VERSION 5.7 ;
BUSBITCHARS "[]" ;
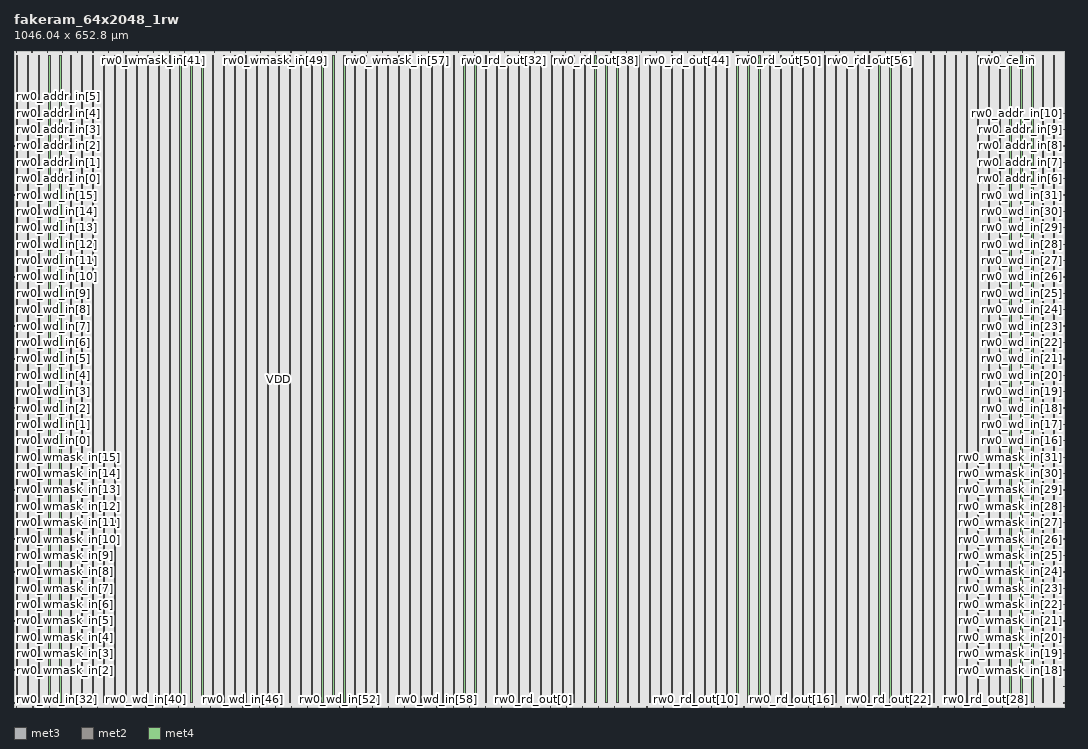
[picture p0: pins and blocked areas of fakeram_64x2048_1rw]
MACRO fakeram_64x2048_1rw
  FOREIGN fakeram_64x2048_1rw 0 0 ;
  SYMMETRY X Y R90 ;
  SIZE 1046.040 BY 652.800 ;
  CLASS BLOCK ;
  PIN rw0_wmask_in[0]
    DIRECTION INPUT ;
    USE SIGNAL ;
    SHAPE ABUTMENT ;
    PORT
      LAYER met3 ;
      RECT 0.000 3.930 0.900 4.230 ;
    END
  END rw0_wmask_in[0]
  PIN rw0_wmask_in[1]
    DIRECTION INPUT ;
    USE SIGNAL ;
    SHAPE ABUTMENT ;
    PORT
      LAYER met3 ;
      RECT 0.000 20.250 0.900 20.550 ;
    END
  END rw0_wmask_in[1]
  PIN rw0_wmask_in[2]
    DIRECTION INPUT ;
    USE SIGNAL ;
    SHAPE ABUTMENT ;
    PORT
      LAYER met3 ;
      RECT 0.000 36.570 0.900 36.870 ;
    END
  END rw0_wmask_in[2]
  PIN rw0_wmask_in[3]
    DIRECTION INPUT ;
    USE SIGNAL ;
    SHAPE ABUTMENT ;
    PORT
      LAYER met3 ;
      RECT 0.000 52.890 0.900 53.190 ;
    END
  END rw0_wmask_in[3]
  PIN rw0_wmask_in[4]
    DIRECTION INPUT ;
    USE SIGNAL ;
    SHAPE ABUTMENT ;
    PORT
      LAYER met3 ;
      RECT 0.000 69.210 0.900 69.510 ;
    END
  END rw0_wmask_in[4]
  PIN rw0_wmask_in[5]
    DIRECTION INPUT ;
    USE SIGNAL ;
    SHAPE ABUTMENT ;
    PORT
      LAYER met3 ;
      RECT 0.000 85.530 0.900 85.830 ;
    END
  END rw0_wmask_in[5]
  PIN rw0_wmask_in[6]
    DIRECTION INPUT ;
    USE SIGNAL ;
    SHAPE ABUTMENT ;
    PORT
      LAYER met3 ;
      RECT 0.000 101.850 0.900 102.150 ;
    END
  END rw0_wmask_in[6]
  PIN rw0_wmask_in[7]
    DIRECTION INPUT ;
    USE SIGNAL ;
    SHAPE ABUTMENT ;
    PORT
      LAYER met3 ;
      RECT 0.000 118.170 0.900 118.470 ;
    END
  END rw0_wmask_in[7]
  PIN rw0_wmask_in[8]
    DIRECTION INPUT ;
    USE SIGNAL ;
    SHAPE ABUTMENT ;
    PORT
      LAYER met3 ;
      RECT 0.000 134.490 0.900 134.790 ;
    END
  END rw0_wmask_in[8]
  PIN rw0_wmask_in[9]
    DIRECTION INPUT ;
    USE SIGNAL ;
    SHAPE ABUTMENT ;
    PORT
      LAYER met3 ;
      RECT 0.000 150.810 0.900 151.110 ;
    END
  END rw0_wmask_in[9]
  PIN rw0_wmask_in[10]
    DIRECTION INPUT ;
    USE SIGNAL ;
    SHAPE ABUTMENT ;
    PORT
      LAYER met3 ;
      RECT 0.000 167.130 0.900 167.430 ;
    END
  END rw0_wmask_in[10]
  PIN rw0_wmask_in[11]
    DIRECTION INPUT ;
    USE SIGNAL ;
    SHAPE ABUTMENT ;
    PORT
      LAYER met3 ;
      RECT 0.000 183.450 0.900 183.750 ;
    END
  END rw0_wmask_in[11]
  PIN rw0_wmask_in[12]
    DIRECTION INPUT ;
    USE SIGNAL ;
    SHAPE ABUTMENT ;
    PORT
      LAYER met3 ;
      RECT 0.000 199.770 0.900 200.070 ;
    END
  END rw0_wmask_in[12]
  PIN rw0_wmask_in[13]
    DIRECTION INPUT ;
    USE SIGNAL ;
    SHAPE ABUTMENT ;
    PORT
      LAYER met3 ;
      RECT 0.000 216.090 0.900 216.390 ;
    END
  END rw0_wmask_in[13]
  PIN rw0_wmask_in[14]
    DIRECTION INPUT ;
    USE SIGNAL ;
    SHAPE ABUTMENT ;
    PORT
      LAYER met3 ;
      RECT 0.000 232.410 0.900 232.710 ;
    END
  END rw0_wmask_in[14]
  PIN rw0_wmask_in[15]
    DIRECTION INPUT ;
    USE SIGNAL ;
    SHAPE ABUTMENT ;
    PORT
      LAYER met3 ;
      RECT 0.000 248.730 0.900 249.030 ;
    END
  END rw0_wmask_in[15]
  PIN rw0_wmask_in[16]
    DIRECTION INPUT ;
    USE SIGNAL ;
    SHAPE ABUTMENT ;
    PORT
      LAYER met3 ;
      RECT 1045.140 3.930 1046.040 4.230 ;
    END
  END rw0_wmask_in[16]
  PIN rw0_wmask_in[17]
    DIRECTION INPUT ;
    USE SIGNAL ;
    SHAPE ABUTMENT ;
    PORT
      LAYER met3 ;
      RECT 1045.140 20.250 1046.040 20.550 ;
    END
  END rw0_wmask_in[17]
  PIN rw0_wmask_in[18]
    DIRECTION INPUT ;
    USE SIGNAL ;
    SHAPE ABUTMENT ;
    PORT
      LAYER met3 ;
      RECT 1045.140 36.570 1046.040 36.870 ;
    END
  END rw0_wmask_in[18]
  PIN rw0_wmask_in[19]
    DIRECTION INPUT ;
    USE SIGNAL ;
    SHAPE ABUTMENT ;
    PORT
      LAYER met3 ;
      RECT 1045.140 52.890 1046.040 53.190 ;
    END
  END rw0_wmask_in[19]
  PIN rw0_wmask_in[20]
    DIRECTION INPUT ;
    USE SIGNAL ;
    SHAPE ABUTMENT ;
    PORT
      LAYER met3 ;
      RECT 1045.140 69.210 1046.040 69.510 ;
    END
  END rw0_wmask_in[20]
  PIN rw0_wmask_in[21]
    DIRECTION INPUT ;
    USE SIGNAL ;
    SHAPE ABUTMENT ;
    PORT
      LAYER met3 ;
      RECT 1045.140 85.530 1046.040 85.830 ;
    END
  END rw0_wmask_in[21]
  PIN rw0_wmask_in[22]
    DIRECTION INPUT ;
    USE SIGNAL ;
    SHAPE ABUTMENT ;
    PORT
      LAYER met3 ;
      RECT 1045.140 101.850 1046.040 102.150 ;
    END
  END rw0_wmask_in[22]
  PIN rw0_wmask_in[23]
    DIRECTION INPUT ;
    USE SIGNAL ;
    SHAPE ABUTMENT ;
    PORT
      LAYER met3 ;
      RECT 1045.140 118.170 1046.040 118.470 ;
    END
  END rw0_wmask_in[23]
  PIN rw0_wmask_in[24]
    DIRECTION INPUT ;
    USE SIGNAL ;
    SHAPE ABUTMENT ;
    PORT
      LAYER met3 ;
      RECT 1045.140 134.490 1046.040 134.790 ;
    END
  END rw0_wmask_in[24]
  PIN rw0_wmask_in[25]
    DIRECTION INPUT ;
    USE SIGNAL ;
    SHAPE ABUTMENT ;
    PORT
      LAYER met3 ;
      RECT 1045.140 150.810 1046.040 151.110 ;
    END
  END rw0_wmask_in[25]
  PIN rw0_wmask_in[26]
    DIRECTION INPUT ;
    USE SIGNAL ;
    SHAPE ABUTMENT ;
    PORT
      LAYER met3 ;
      RECT 1045.140 167.130 1046.040 167.430 ;
    END
  END rw0_wmask_in[26]
  PIN rw0_wmask_in[27]
    DIRECTION INPUT ;
    USE SIGNAL ;
    SHAPE ABUTMENT ;
    PORT
      LAYER met3 ;
      RECT 1045.140 183.450 1046.040 183.750 ;
    END
  END rw0_wmask_in[27]
  PIN rw0_wmask_in[28]
    DIRECTION INPUT ;
    USE SIGNAL ;
    SHAPE ABUTMENT ;
    PORT
      LAYER met3 ;
      RECT 1045.140 199.770 1046.040 200.070 ;
    END
  END rw0_wmask_in[28]
  PIN rw0_wmask_in[29]
    DIRECTION INPUT ;
    USE SIGNAL ;
    SHAPE ABUTMENT ;
    PORT
      LAYER met3 ;
      RECT 1045.140 216.090 1046.040 216.390 ;
    END
  END rw0_wmask_in[29]
  PIN rw0_wmask_in[30]
    DIRECTION INPUT ;
    USE SIGNAL ;
    SHAPE ABUTMENT ;
    PORT
      LAYER met3 ;
      RECT 1045.140 232.410 1046.040 232.710 ;
    END
  END rw0_wmask_in[30]
  PIN rw0_wmask_in[31]
    DIRECTION INPUT ;
    USE SIGNAL ;
    SHAPE ABUTMENT ;
    PORT
      LAYER met3 ;
      RECT 1045.140 248.730 1046.040 249.030 ;
    END
  END rw0_wmask_in[31]
  PIN rw0_wmask_in[32]
    DIRECTION INPUT ;
    USE SIGNAL ;
    SHAPE ABUTMENT ;
    PORT
      LAYER met2 ;
      RECT 2.690 652.380 2.830 652.800 ;
    END
  END rw0_wmask_in[32]
  PIN rw0_wmask_in[33]
    DIRECTION INPUT ;
    USE SIGNAL ;
    SHAPE ABUTMENT ;
    PORT
      LAYER met2 ;
      RECT 17.870 652.380 18.010 652.800 ;
    END
  END rw0_wmask_in[33]
  PIN rw0_wmask_in[34]
    DIRECTION INPUT ;
    USE SIGNAL ;
    SHAPE ABUTMENT ;
    PORT
      LAYER met2 ;
      RECT 33.050 652.380 33.190 652.800 ;
    END
  END rw0_wmask_in[34]
  PIN rw0_wmask_in[35]
    DIRECTION INPUT ;
    USE SIGNAL ;
    SHAPE ABUTMENT ;
    PORT
      LAYER met2 ;
      RECT 48.230 652.380 48.370 652.800 ;
    END
  END rw0_wmask_in[35]
  PIN rw0_wmask_in[36]
    DIRECTION INPUT ;
    USE SIGNAL ;
    SHAPE ABUTMENT ;
    PORT
      LAYER met2 ;
      RECT 63.410 652.380 63.550 652.800 ;
    END
  END rw0_wmask_in[36]
  PIN rw0_wmask_in[37]
    DIRECTION INPUT ;
    USE SIGNAL ;
    SHAPE ABUTMENT ;
    PORT
      LAYER met2 ;
      RECT 78.590 652.380 78.730 652.800 ;
    END
  END rw0_wmask_in[37]
  PIN rw0_wmask_in[38]
    DIRECTION INPUT ;
    USE SIGNAL ;
    SHAPE ABUTMENT ;
    PORT
      LAYER met2 ;
      RECT 93.770 652.380 93.910 652.800 ;
    END
  END rw0_wmask_in[38]
  PIN rw0_wmask_in[39]
    DIRECTION INPUT ;
    USE SIGNAL ;
    SHAPE ABUTMENT ;
    PORT
      LAYER met2 ;
      RECT 108.950 652.380 109.090 652.800 ;
    END
  END rw0_wmask_in[39]
  PIN rw0_wmask_in[40]
    DIRECTION INPUT ;
    USE SIGNAL ;
    SHAPE ABUTMENT ;
    PORT
      LAYER met2 ;
      RECT 124.130 652.380 124.270 652.800 ;
    END
  END rw0_wmask_in[40]
  PIN rw0_wmask_in[41]
    DIRECTION INPUT ;
    USE SIGNAL ;
    SHAPE ABUTMENT ;
    PORT
      LAYER met2 ;
      RECT 139.310 652.380 139.450 652.800 ;
    END
  END rw0_wmask_in[41]
  PIN rw0_wmask_in[42]
    DIRECTION INPUT ;
    USE SIGNAL ;
    SHAPE ABUTMENT ;
    PORT
      LAYER met2 ;
      RECT 154.490 652.380 154.630 652.800 ;
    END
  END rw0_wmask_in[42]
  PIN rw0_wmask_in[43]
    DIRECTION INPUT ;
    USE SIGNAL ;
    SHAPE ABUTMENT ;
    PORT
      LAYER met2 ;
      RECT 169.670 652.380 169.810 652.800 ;
    END
  END rw0_wmask_in[43]
  PIN rw0_wmask_in[44]
    DIRECTION INPUT ;
    USE SIGNAL ;
    SHAPE ABUTMENT ;
    PORT
      LAYER met2 ;
      RECT 184.850 652.380 184.990 652.800 ;
    END
  END rw0_wmask_in[44]
  PIN rw0_wmask_in[45]
    DIRECTION INPUT ;
    USE SIGNAL ;
    SHAPE ABUTMENT ;
    PORT
      LAYER met2 ;
      RECT 200.030 652.380 200.170 652.800 ;
    END
  END rw0_wmask_in[45]
  PIN rw0_wmask_in[46]
    DIRECTION INPUT ;
    USE SIGNAL ;
    SHAPE ABUTMENT ;
    PORT
      LAYER met2 ;
      RECT 215.210 652.380 215.350 652.800 ;
    END
  END rw0_wmask_in[46]
  PIN rw0_wmask_in[47]
    DIRECTION INPUT ;
    USE SIGNAL ;
    SHAPE ABUTMENT ;
    PORT
      LAYER met2 ;
      RECT 230.390 652.380 230.530 652.800 ;
    END
  END rw0_wmask_in[47]
  PIN rw0_wmask_in[48]
    DIRECTION INPUT ;
    USE SIGNAL ;
    SHAPE ABUTMENT ;
    PORT
      LAYER met2 ;
      RECT 245.570 652.380 245.710 652.800 ;
    END
  END rw0_wmask_in[48]
  PIN rw0_wmask_in[49]
    DIRECTION INPUT ;
    USE SIGNAL ;
    SHAPE ABUTMENT ;
    PORT
      LAYER met2 ;
      RECT 260.750 652.380 260.890 652.800 ;
    END
  END rw0_wmask_in[49]
  PIN rw0_wmask_in[50]
    DIRECTION INPUT ;
    USE SIGNAL ;
    SHAPE ABUTMENT ;
    PORT
      LAYER met2 ;
      RECT 275.930 652.380 276.070 652.800 ;
    END
  END rw0_wmask_in[50]
  PIN rw0_wmask_in[51]
    DIRECTION INPUT ;
    USE SIGNAL ;
    SHAPE ABUTMENT ;
    PORT
      LAYER met2 ;
      RECT 291.110 652.380 291.250 652.800 ;
    END
  END rw0_wmask_in[51]
  PIN rw0_wmask_in[52]
    DIRECTION INPUT ;
    USE SIGNAL ;
    SHAPE ABUTMENT ;
    PORT
      LAYER met2 ;
      RECT 306.290 652.380 306.430 652.800 ;
    END
  END rw0_wmask_in[52]
  PIN rw0_wmask_in[53]
    DIRECTION INPUT ;
    USE SIGNAL ;
    SHAPE ABUTMENT ;
    PORT
      LAYER met2 ;
      RECT 321.470 652.380 321.610 652.800 ;
    END
  END rw0_wmask_in[53]
  PIN rw0_wmask_in[54]
    DIRECTION INPUT ;
    USE SIGNAL ;
    SHAPE ABUTMENT ;
    PORT
      LAYER met2 ;
      RECT 336.650 652.380 336.790 652.800 ;
    END
  END rw0_wmask_in[54]
  PIN rw0_wmask_in[55]
    DIRECTION INPUT ;
    USE SIGNAL ;
    SHAPE ABUTMENT ;
    PORT
      LAYER met2 ;
      RECT 351.830 652.380 351.970 652.800 ;
    END
  END rw0_wmask_in[55]
  PIN rw0_wmask_in[56]
    DIRECTION INPUT ;
    USE SIGNAL ;
    SHAPE ABUTMENT ;
    PORT
      LAYER met2 ;
      RECT 367.010 652.380 367.150 652.800 ;
    END
  END rw0_wmask_in[56]
  PIN rw0_wmask_in[57]
    DIRECTION INPUT ;
    USE SIGNAL ;
    SHAPE ABUTMENT ;
    PORT
      LAYER met2 ;
      RECT 382.190 652.380 382.330 652.800 ;
    END
  END rw0_wmask_in[57]
  PIN rw0_wmask_in[58]
    DIRECTION INPUT ;
    USE SIGNAL ;
    SHAPE ABUTMENT ;
    PORT
      LAYER met2 ;
      RECT 397.370 652.380 397.510 652.800 ;
    END
  END rw0_wmask_in[58]
  PIN rw0_wmask_in[59]
    DIRECTION INPUT ;
    USE SIGNAL ;
    SHAPE ABUTMENT ;
    PORT
      LAYER met2 ;
      RECT 412.550 652.380 412.690 652.800 ;
    END
  END rw0_wmask_in[59]
  PIN rw0_wmask_in[60]
    DIRECTION INPUT ;
    USE SIGNAL ;
    SHAPE ABUTMENT ;
    PORT
      LAYER met2 ;
      RECT 427.730 652.380 427.870 652.800 ;
    END
  END rw0_wmask_in[60]
  PIN rw0_wmask_in[61]
    DIRECTION INPUT ;
    USE SIGNAL ;
    SHAPE ABUTMENT ;
    PORT
      LAYER met2 ;
      RECT 442.910 652.380 443.050 652.800 ;
    END
  END rw0_wmask_in[61]
  PIN rw0_wmask_in[62]
    DIRECTION INPUT ;
    USE SIGNAL ;
    SHAPE ABUTMENT ;
    PORT
      LAYER met2 ;
      RECT 458.090 652.380 458.230 652.800 ;
    END
  END rw0_wmask_in[62]
  PIN rw0_wmask_in[63]
    DIRECTION INPUT ;
    USE SIGNAL ;
    SHAPE ABUTMENT ;
    PORT
      LAYER met2 ;
      RECT 473.270 652.380 473.410 652.800 ;
    END
  END rw0_wmask_in[63]
  PIN rw0_wd_in[0]
    DIRECTION INPUT ;
    USE SIGNAL ;
    SHAPE ABUTMENT ;
    PORT
      LAYER met3 ;
      RECT 0.000 265.050 0.900 265.350 ;
    END
  END rw0_wd_in[0]
  PIN rw0_wd_in[1]
    DIRECTION INPUT ;
    USE SIGNAL ;
    SHAPE ABUTMENT ;
    PORT
      LAYER met3 ;
      RECT 0.000 281.370 0.900 281.670 ;
    END
  END rw0_wd_in[1]
  PIN rw0_wd_in[2]
    DIRECTION INPUT ;
    USE SIGNAL ;
    SHAPE ABUTMENT ;
    PORT
      LAYER met3 ;
      RECT 0.000 297.690 0.900 297.990 ;
    END
  END rw0_wd_in[2]
  PIN rw0_wd_in[3]
    DIRECTION INPUT ;
    USE SIGNAL ;
    SHAPE ABUTMENT ;
    PORT
      LAYER met3 ;
      RECT 0.000 314.010 0.900 314.310 ;
    END
  END rw0_wd_in[3]
  PIN rw0_wd_in[4]
    DIRECTION INPUT ;
    USE SIGNAL ;
    SHAPE ABUTMENT ;
    PORT
      LAYER met3 ;
      RECT 0.000 330.330 0.900 330.630 ;
    END
  END rw0_wd_in[4]
  PIN rw0_wd_in[5]
    DIRECTION INPUT ;
    USE SIGNAL ;
    SHAPE ABUTMENT ;
    PORT
      LAYER met3 ;
      RECT 0.000 346.650 0.900 346.950 ;
    END
  END rw0_wd_in[5]
  PIN rw0_wd_in[6]
    DIRECTION INPUT ;
    USE SIGNAL ;
    SHAPE ABUTMENT ;
    PORT
      LAYER met3 ;
      RECT 0.000 362.970 0.900 363.270 ;
    END
  END rw0_wd_in[6]
  PIN rw0_wd_in[7]
    DIRECTION INPUT ;
    USE SIGNAL ;
    SHAPE ABUTMENT ;
    PORT
      LAYER met3 ;
      RECT 0.000 379.290 0.900 379.590 ;
    END
  END rw0_wd_in[7]
  PIN rw0_wd_in[8]
    DIRECTION INPUT ;
    USE SIGNAL ;
    SHAPE ABUTMENT ;
    PORT
      LAYER met3 ;
      RECT 0.000 395.610 0.900 395.910 ;
    END
  END rw0_wd_in[8]
  PIN rw0_wd_in[9]
    DIRECTION INPUT ;
    USE SIGNAL ;
    SHAPE ABUTMENT ;
    PORT
      LAYER met3 ;
      RECT 0.000 411.930 0.900 412.230 ;
    END
  END rw0_wd_in[9]
  PIN rw0_wd_in[10]
    DIRECTION INPUT ;
    USE SIGNAL ;
    SHAPE ABUTMENT ;
    PORT
      LAYER met3 ;
      RECT 0.000 428.250 0.900 428.550 ;
    END
  END rw0_wd_in[10]
  PIN rw0_wd_in[11]
    DIRECTION INPUT ;
    USE SIGNAL ;
    SHAPE ABUTMENT ;
    PORT
      LAYER met3 ;
      RECT 0.000 444.570 0.900 444.870 ;
    END
  END rw0_wd_in[11]
  PIN rw0_wd_in[12]
    DIRECTION INPUT ;
    USE SIGNAL ;
    SHAPE ABUTMENT ;
    PORT
      LAYER met3 ;
      RECT 0.000 460.890 0.900 461.190 ;
    END
  END rw0_wd_in[12]
  PIN rw0_wd_in[13]
    DIRECTION INPUT ;
    USE SIGNAL ;
    SHAPE ABUTMENT ;
    PORT
      LAYER met3 ;
      RECT 0.000 477.210 0.900 477.510 ;
    END
  END rw0_wd_in[13]
  PIN rw0_wd_in[14]
    DIRECTION INPUT ;
    USE SIGNAL ;
    SHAPE ABUTMENT ;
    PORT
      LAYER met3 ;
      RECT 0.000 493.530 0.900 493.830 ;
    END
  END rw0_wd_in[14]
  PIN rw0_wd_in[15]
    DIRECTION INPUT ;
    USE SIGNAL ;
    SHAPE ABUTMENT ;
    PORT
      LAYER met3 ;
      RECT 0.000 509.850 0.900 510.150 ;
    END
  END rw0_wd_in[15]
  PIN rw0_wd_in[16]
    DIRECTION INPUT ;
    USE SIGNAL ;
    SHAPE ABUTMENT ;
    PORT
      LAYER met3 ;
      RECT 1045.140 265.050 1046.040 265.350 ;
    END
  END rw0_wd_in[16]
  PIN rw0_wd_in[17]
    DIRECTION INPUT ;
    USE SIGNAL ;
    SHAPE ABUTMENT ;
    PORT
      LAYER met3 ;
      RECT 1045.140 281.370 1046.040 281.670 ;
    END
  END rw0_wd_in[17]
  PIN rw0_wd_in[18]
    DIRECTION INPUT ;
    USE SIGNAL ;
    SHAPE ABUTMENT ;
    PORT
      LAYER met3 ;
      RECT 1045.140 297.690 1046.040 297.990 ;
    END
  END rw0_wd_in[18]
  PIN rw0_wd_in[19]
    DIRECTION INPUT ;
    USE SIGNAL ;
    SHAPE ABUTMENT ;
    PORT
      LAYER met3 ;
      RECT 1045.140 314.010 1046.040 314.310 ;
    END
  END rw0_wd_in[19]
  PIN rw0_wd_in[20]
    DIRECTION INPUT ;
    USE SIGNAL ;
    SHAPE ABUTMENT ;
    PORT
      LAYER met3 ;
      RECT 1045.140 330.330 1046.040 330.630 ;
    END
  END rw0_wd_in[20]
  PIN rw0_wd_in[21]
    DIRECTION INPUT ;
    USE SIGNAL ;
    SHAPE ABUTMENT ;
    PORT
      LAYER met3 ;
      RECT 1045.140 346.650 1046.040 346.950 ;
    END
  END rw0_wd_in[21]
  PIN rw0_wd_in[22]
    DIRECTION INPUT ;
    USE SIGNAL ;
    SHAPE ABUTMENT ;
    PORT
      LAYER met3 ;
      RECT 1045.140 362.970 1046.040 363.270 ;
    END
  END rw0_wd_in[22]
  PIN rw0_wd_in[23]
    DIRECTION INPUT ;
    USE SIGNAL ;
    SHAPE ABUTMENT ;
    PORT
      LAYER met3 ;
      RECT 1045.140 379.290 1046.040 379.590 ;
    END
  END rw0_wd_in[23]
  PIN rw0_wd_in[24]
    DIRECTION INPUT ;
    USE SIGNAL ;
    SHAPE ABUTMENT ;
    PORT
      LAYER met3 ;
      RECT 1045.140 395.610 1046.040 395.910 ;
    END
  END rw0_wd_in[24]
  PIN rw0_wd_in[25]
    DIRECTION INPUT ;
    USE SIGNAL ;
    SHAPE ABUTMENT ;
    PORT
      LAYER met3 ;
      RECT 1045.140 411.930 1046.040 412.230 ;
    END
  END rw0_wd_in[25]
  PIN rw0_wd_in[26]
    DIRECTION INPUT ;
    USE SIGNAL ;
    SHAPE ABUTMENT ;
    PORT
      LAYER met3 ;
      RECT 1045.140 428.250 1046.040 428.550 ;
    END
  END rw0_wd_in[26]
  PIN rw0_wd_in[27]
    DIRECTION INPUT ;
    USE SIGNAL ;
    SHAPE ABUTMENT ;
    PORT
      LAYER met3 ;
      RECT 1045.140 444.570 1046.040 444.870 ;
    END
  END rw0_wd_in[27]
  PIN rw0_wd_in[28]
    DIRECTION INPUT ;
    USE SIGNAL ;
    SHAPE ABUTMENT ;
    PORT
      LAYER met3 ;
      RECT 1045.140 460.890 1046.040 461.190 ;
    END
  END rw0_wd_in[28]
  PIN rw0_wd_in[29]
    DIRECTION INPUT ;
    USE SIGNAL ;
    SHAPE ABUTMENT ;
    PORT
      LAYER met3 ;
      RECT 1045.140 477.210 1046.040 477.510 ;
    END
  END rw0_wd_in[29]
  PIN rw0_wd_in[30]
    DIRECTION INPUT ;
    USE SIGNAL ;
    SHAPE ABUTMENT ;
    PORT
      LAYER met3 ;
      RECT 1045.140 493.530 1046.040 493.830 ;
    END
  END rw0_wd_in[30]
  PIN rw0_wd_in[31]
    DIRECTION INPUT ;
    USE SIGNAL ;
    SHAPE ABUTMENT ;
    PORT
      LAYER met3 ;
      RECT 1045.140 509.850 1046.040 510.150 ;
    END
  END rw0_wd_in[31]
  PIN rw0_wd_in[32]
    DIRECTION OUTPUT ;
    USE SIGNAL ;
    SHAPE ABUTMENT ;
    PORT
      LAYER met2 ;
      RECT 2.690 0.000 2.830 0.420 ;
    END
  END rw0_wd_in[32]
  PIN rw0_wd_in[33]
    DIRECTION OUTPUT ;
    USE SIGNAL ;
    SHAPE ABUTMENT ;
    PORT
      LAYER met2 ;
      RECT 18.790 0.000 18.930 0.420 ;
    END
  END rw0_wd_in[33]
  PIN rw0_wd_in[34]
    DIRECTION OUTPUT ;
    USE SIGNAL ;
    SHAPE ABUTMENT ;
    PORT
      LAYER met2 ;
      RECT 34.890 0.000 35.030 0.420 ;
    END
  END rw0_wd_in[34]
  PIN rw0_wd_in[35]
    DIRECTION OUTPUT ;
    USE SIGNAL ;
    SHAPE ABUTMENT ;
    PORT
      LAYER met2 ;
      RECT 50.990 0.000 51.130 0.420 ;
    END
  END rw0_wd_in[35]
  PIN rw0_wd_in[36]
    DIRECTION OUTPUT ;
    USE SIGNAL ;
    SHAPE ABUTMENT ;
    PORT
      LAYER met2 ;
      RECT 67.090 0.000 67.230 0.420 ;
    END
  END rw0_wd_in[36]
  PIN rw0_wd_in[37]
    DIRECTION OUTPUT ;
    USE SIGNAL ;
    SHAPE ABUTMENT ;
    PORT
      LAYER met2 ;
      RECT 83.190 0.000 83.330 0.420 ;
    END
  END rw0_wd_in[37]
  PIN rw0_wd_in[38]
    DIRECTION OUTPUT ;
    USE SIGNAL ;
    SHAPE ABUTMENT ;
    PORT
      LAYER met2 ;
      RECT 99.290 0.000 99.430 0.420 ;
    END
  END rw0_wd_in[38]
  PIN rw0_wd_in[39]
    DIRECTION OUTPUT ;
    USE SIGNAL ;
    SHAPE ABUTMENT ;
    PORT
      LAYER met2 ;
      RECT 115.390 0.000 115.530 0.420 ;
    END
  END rw0_wd_in[39]
  PIN rw0_wd_in[40]
    DIRECTION OUTPUT ;
    USE SIGNAL ;
    SHAPE ABUTMENT ;
    PORT
      LAYER met2 ;
      RECT 131.490 0.000 131.630 0.420 ;
    END
  END rw0_wd_in[40]
  PIN rw0_wd_in[41]
    DIRECTION OUTPUT ;
    USE SIGNAL ;
    SHAPE ABUTMENT ;
    PORT
      LAYER met2 ;
      RECT 147.590 0.000 147.730 0.420 ;
    END
  END rw0_wd_in[41]
  PIN rw0_wd_in[42]
    DIRECTION OUTPUT ;
    USE SIGNAL ;
    SHAPE ABUTMENT ;
    PORT
      LAYER met2 ;
      RECT 163.690 0.000 163.830 0.420 ;
    END
  END rw0_wd_in[42]
  PIN rw0_wd_in[43]
    DIRECTION OUTPUT ;
    USE SIGNAL ;
    SHAPE ABUTMENT ;
    PORT
      LAYER met2 ;
      RECT 179.790 0.000 179.930 0.420 ;
    END
  END rw0_wd_in[43]
  PIN rw0_wd_in[44]
    DIRECTION OUTPUT ;
    USE SIGNAL ;
    SHAPE ABUTMENT ;
    PORT
      LAYER met2 ;
      RECT 195.890 0.000 196.030 0.420 ;
    END
  END rw0_wd_in[44]
  PIN rw0_wd_in[45]
    DIRECTION OUTPUT ;
    USE SIGNAL ;
    SHAPE ABUTMENT ;
    PORT
      LAYER met2 ;
      RECT 211.990 0.000 212.130 0.420 ;
    END
  END rw0_wd_in[45]
  PIN rw0_wd_in[46]
    DIRECTION OUTPUT ;
    USE SIGNAL ;
    SHAPE ABUTMENT ;
    PORT
      LAYER met2 ;
      RECT 228.090 0.000 228.230 0.420 ;
    END
  END rw0_wd_in[46]
  PIN rw0_wd_in[47]
    DIRECTION OUTPUT ;
    USE SIGNAL ;
    SHAPE ABUTMENT ;
    PORT
      LAYER met2 ;
      RECT 244.190 0.000 244.330 0.420 ;
    END
  END rw0_wd_in[47]
  PIN rw0_wd_in[48]
    DIRECTION OUTPUT ;
    USE SIGNAL ;
    SHAPE ABUTMENT ;
    PORT
      LAYER met2 ;
      RECT 260.290 0.000 260.430 0.420 ;
    END
  END rw0_wd_in[48]
  PIN rw0_wd_in[49]
    DIRECTION OUTPUT ;
    USE SIGNAL ;
    SHAPE ABUTMENT ;
    PORT
      LAYER met2 ;
      RECT 276.390 0.000 276.530 0.420 ;
    END
  END rw0_wd_in[49]
  PIN rw0_wd_in[50]
    DIRECTION OUTPUT ;
    USE SIGNAL ;
    SHAPE ABUTMENT ;
    PORT
      LAYER met2 ;
      RECT 292.490 0.000 292.630 0.420 ;
    END
  END rw0_wd_in[50]
  PIN rw0_wd_in[51]
    DIRECTION OUTPUT ;
    USE SIGNAL ;
    SHAPE ABUTMENT ;
    PORT
      LAYER met2 ;
      RECT 308.590 0.000 308.730 0.420 ;
    END
  END rw0_wd_in[51]
  PIN rw0_wd_in[52]
    DIRECTION OUTPUT ;
    USE SIGNAL ;
    SHAPE ABUTMENT ;
    PORT
      LAYER met2 ;
      RECT 324.690 0.000 324.830 0.420 ;
    END
  END rw0_wd_in[52]
  PIN rw0_wd_in[53]
    DIRECTION OUTPUT ;
    USE SIGNAL ;
    SHAPE ABUTMENT ;
    PORT
      LAYER met2 ;
      RECT 340.790 0.000 340.930 0.420 ;
    END
  END rw0_wd_in[53]
  PIN rw0_wd_in[54]
    DIRECTION OUTPUT ;
    USE SIGNAL ;
    SHAPE ABUTMENT ;
    PORT
      LAYER met2 ;
      RECT 356.890 0.000 357.030 0.420 ;
    END
  END rw0_wd_in[54]
  PIN rw0_wd_in[55]
    DIRECTION OUTPUT ;
    USE SIGNAL ;
    SHAPE ABUTMENT ;
    PORT
      LAYER met2 ;
      RECT 372.990 0.000 373.130 0.420 ;
    END
  END rw0_wd_in[55]
  PIN rw0_wd_in[56]
    DIRECTION OUTPUT ;
    USE SIGNAL ;
    SHAPE ABUTMENT ;
    PORT
      LAYER met2 ;
      RECT 389.090 0.000 389.230 0.420 ;
    END
  END rw0_wd_in[56]
  PIN rw0_wd_in[57]
    DIRECTION OUTPUT ;
    USE SIGNAL ;
    SHAPE ABUTMENT ;
    PORT
      LAYER met2 ;
      RECT 405.190 0.000 405.330 0.420 ;
    END
  END rw0_wd_in[57]
  PIN rw0_wd_in[58]
    DIRECTION OUTPUT ;
    USE SIGNAL ;
    SHAPE ABUTMENT ;
    PORT
      LAYER met2 ;
      RECT 421.290 0.000 421.430 0.420 ;
    END
  END rw0_wd_in[58]
  PIN rw0_wd_in[59]
    DIRECTION OUTPUT ;
    USE SIGNAL ;
    SHAPE ABUTMENT ;
    PORT
      LAYER met2 ;
      RECT 437.390 0.000 437.530 0.420 ;
    END
  END rw0_wd_in[59]
  PIN rw0_wd_in[60]
    DIRECTION OUTPUT ;
    USE SIGNAL ;
    SHAPE ABUTMENT ;
    PORT
      LAYER met2 ;
      RECT 453.490 0.000 453.630 0.420 ;
    END
  END rw0_wd_in[60]
  PIN rw0_wd_in[61]
    DIRECTION OUTPUT ;
    USE SIGNAL ;
    SHAPE ABUTMENT ;
    PORT
      LAYER met2 ;
      RECT 469.590 0.000 469.730 0.420 ;
    END
  END rw0_wd_in[61]
  PIN rw0_wd_in[62]
    DIRECTION OUTPUT ;
    USE SIGNAL ;
    SHAPE ABUTMENT ;
    PORT
      LAYER met2 ;
      RECT 485.690 0.000 485.830 0.420 ;
    END
  END rw0_wd_in[62]
  PIN rw0_wd_in[63]
    DIRECTION OUTPUT ;
    USE SIGNAL ;
    SHAPE ABUTMENT ;
    PORT
      LAYER met2 ;
      RECT 501.790 0.000 501.930 0.420 ;
    END
  END rw0_wd_in[63]
  PIN rw0_rd_out[0]
    DIRECTION OUTPUT ;
    USE SIGNAL ;
    SHAPE ABUTMENT ;
    PORT
      LAYER met2 ;
      RECT 517.890 0.000 518.030 0.420 ;
    END
  END rw0_rd_out[0]
  PIN rw0_rd_out[1]
    DIRECTION OUTPUT ;
    USE SIGNAL ;
    SHAPE ABUTMENT ;
    PORT
      LAYER met2 ;
      RECT 533.990 0.000 534.130 0.420 ;
    END
  END rw0_rd_out[1]
  PIN rw0_rd_out[2]
    DIRECTION OUTPUT ;
    USE SIGNAL ;
    SHAPE ABUTMENT ;
    PORT
      LAYER met2 ;
      RECT 550.090 0.000 550.230 0.420 ;
    END
  END rw0_rd_out[2]
  PIN rw0_rd_out[3]
    DIRECTION OUTPUT ;
    USE SIGNAL ;
    SHAPE ABUTMENT ;
    PORT
      LAYER met2 ;
      RECT 566.190 0.000 566.330 0.420 ;
    END
  END rw0_rd_out[3]
  PIN rw0_rd_out[4]
    DIRECTION OUTPUT ;
    USE SIGNAL ;
    SHAPE ABUTMENT ;
    PORT
      LAYER met2 ;
      RECT 582.290 0.000 582.430 0.420 ;
    END
  END rw0_rd_out[4]
  PIN rw0_rd_out[5]
    DIRECTION OUTPUT ;
    USE SIGNAL ;
    SHAPE ABUTMENT ;
    PORT
      LAYER met2 ;
      RECT 598.390 0.000 598.530 0.420 ;
    END
  END rw0_rd_out[5]
  PIN rw0_rd_out[6]
    DIRECTION OUTPUT ;
    USE SIGNAL ;
    SHAPE ABUTMENT ;
    PORT
      LAYER met2 ;
      RECT 614.490 0.000 614.630 0.420 ;
    END
  END rw0_rd_out[6]
  PIN rw0_rd_out[7]
    DIRECTION OUTPUT ;
    USE SIGNAL ;
    SHAPE ABUTMENT ;
    PORT
      LAYER met2 ;
      RECT 630.590 0.000 630.730 0.420 ;
    END
  END rw0_rd_out[7]
  PIN rw0_rd_out[8]
    DIRECTION OUTPUT ;
    USE SIGNAL ;
    SHAPE ABUTMENT ;
    PORT
      LAYER met2 ;
      RECT 646.690 0.000 646.830 0.420 ;
    END
  END rw0_rd_out[8]
  PIN rw0_rd_out[9]
    DIRECTION OUTPUT ;
    USE SIGNAL ;
    SHAPE ABUTMENT ;
    PORT
      LAYER met2 ;
      RECT 662.790 0.000 662.930 0.420 ;
    END
  END rw0_rd_out[9]
  PIN rw0_rd_out[10]
    DIRECTION OUTPUT ;
    USE SIGNAL ;
    SHAPE ABUTMENT ;
    PORT
      LAYER met2 ;
      RECT 678.890 0.000 679.030 0.420 ;
    END
  END rw0_rd_out[10]
  PIN rw0_rd_out[11]
    DIRECTION OUTPUT ;
    USE SIGNAL ;
    SHAPE ABUTMENT ;
    PORT
      LAYER met2 ;
      RECT 694.990 0.000 695.130 0.420 ;
    END
  END rw0_rd_out[11]
  PIN rw0_rd_out[12]
    DIRECTION OUTPUT ;
    USE SIGNAL ;
    SHAPE ABUTMENT ;
    PORT
      LAYER met2 ;
      RECT 711.090 0.000 711.230 0.420 ;
    END
  END rw0_rd_out[12]
  PIN rw0_rd_out[13]
    DIRECTION OUTPUT ;
    USE SIGNAL ;
    SHAPE ABUTMENT ;
    PORT
      LAYER met2 ;
      RECT 727.190 0.000 727.330 0.420 ;
    END
  END rw0_rd_out[13]
  PIN rw0_rd_out[14]
    DIRECTION OUTPUT ;
    USE SIGNAL ;
    SHAPE ABUTMENT ;
    PORT
      LAYER met2 ;
      RECT 743.290 0.000 743.430 0.420 ;
    END
  END rw0_rd_out[14]
  PIN rw0_rd_out[15]
    DIRECTION OUTPUT ;
    USE SIGNAL ;
    SHAPE ABUTMENT ;
    PORT
      LAYER met2 ;
      RECT 759.390 0.000 759.530 0.420 ;
    END
  END rw0_rd_out[15]
  PIN rw0_rd_out[16]
    DIRECTION OUTPUT ;
    USE SIGNAL ;
    SHAPE ABUTMENT ;
    PORT
      LAYER met2 ;
      RECT 775.490 0.000 775.630 0.420 ;
    END
  END rw0_rd_out[16]
  PIN rw0_rd_out[17]
    DIRECTION OUTPUT ;
    USE SIGNAL ;
    SHAPE ABUTMENT ;
    PORT
      LAYER met2 ;
      RECT 791.590 0.000 791.730 0.420 ;
    END
  END rw0_rd_out[17]
  PIN rw0_rd_out[18]
    DIRECTION OUTPUT ;
    USE SIGNAL ;
    SHAPE ABUTMENT ;
    PORT
      LAYER met2 ;
      RECT 807.690 0.000 807.830 0.420 ;
    END
  END rw0_rd_out[18]
  PIN rw0_rd_out[19]
    DIRECTION OUTPUT ;
    USE SIGNAL ;
    SHAPE ABUTMENT ;
    PORT
      LAYER met2 ;
      RECT 823.790 0.000 823.930 0.420 ;
    END
  END rw0_rd_out[19]
  PIN rw0_rd_out[20]
    DIRECTION OUTPUT ;
    USE SIGNAL ;
    SHAPE ABUTMENT ;
    PORT
      LAYER met2 ;
      RECT 839.890 0.000 840.030 0.420 ;
    END
  END rw0_rd_out[20]
  PIN rw0_rd_out[21]
    DIRECTION OUTPUT ;
    USE SIGNAL ;
    SHAPE ABUTMENT ;
    PORT
      LAYER met2 ;
      RECT 855.990 0.000 856.130 0.420 ;
    END
  END rw0_rd_out[21]
  PIN rw0_rd_out[22]
    DIRECTION OUTPUT ;
    USE SIGNAL ;
    SHAPE ABUTMENT ;
    PORT
      LAYER met2 ;
      RECT 872.090 0.000 872.230 0.420 ;
    END
  END rw0_rd_out[22]
  PIN rw0_rd_out[23]
    DIRECTION OUTPUT ;
    USE SIGNAL ;
    SHAPE ABUTMENT ;
    PORT
      LAYER met2 ;
      RECT 888.190 0.000 888.330 0.420 ;
    END
  END rw0_rd_out[23]
  PIN rw0_rd_out[24]
    DIRECTION OUTPUT ;
    USE SIGNAL ;
    SHAPE ABUTMENT ;
    PORT
      LAYER met2 ;
      RECT 904.290 0.000 904.430 0.420 ;
    END
  END rw0_rd_out[24]
  PIN rw0_rd_out[25]
    DIRECTION OUTPUT ;
    USE SIGNAL ;
    SHAPE ABUTMENT ;
    PORT
      LAYER met2 ;
      RECT 920.390 0.000 920.530 0.420 ;
    END
  END rw0_rd_out[25]
  PIN rw0_rd_out[26]
    DIRECTION OUTPUT ;
    USE SIGNAL ;
    SHAPE ABUTMENT ;
    PORT
      LAYER met2 ;
      RECT 936.490 0.000 936.630 0.420 ;
    END
  END rw0_rd_out[26]
  PIN rw0_rd_out[27]
    DIRECTION OUTPUT ;
    USE SIGNAL ;
    SHAPE ABUTMENT ;
    PORT
      LAYER met2 ;
      RECT 952.590 0.000 952.730 0.420 ;
    END
  END rw0_rd_out[27]
  PIN rw0_rd_out[28]
    DIRECTION OUTPUT ;
    USE SIGNAL ;
    SHAPE ABUTMENT ;
    PORT
      LAYER met2 ;
      RECT 968.690 0.000 968.830 0.420 ;
    END
  END rw0_rd_out[28]
  PIN rw0_rd_out[29]
    DIRECTION OUTPUT ;
    USE SIGNAL ;
    SHAPE ABUTMENT ;
    PORT
      LAYER met2 ;
      RECT 984.790 0.000 984.930 0.420 ;
    END
  END rw0_rd_out[29]
  PIN rw0_rd_out[30]
    DIRECTION OUTPUT ;
    USE SIGNAL ;
    SHAPE ABUTMENT ;
    PORT
      LAYER met2 ;
      RECT 1000.890 0.000 1001.030 0.420 ;
    END
  END rw0_rd_out[30]
  PIN rw0_rd_out[31]
    DIRECTION OUTPUT ;
    USE SIGNAL ;
    SHAPE ABUTMENT ;
    PORT
      LAYER met2 ;
      RECT 1016.990 0.000 1017.130 0.420 ;
    END
  END rw0_rd_out[31]
  PIN rw0_rd_out[32]
    DIRECTION OUTPUT ;
    USE SIGNAL ;
    SHAPE ABUTMENT ;
    PORT
      LAYER met2 ;
      RECT 488.450 652.380 488.590 652.800 ;
    END
  END rw0_rd_out[32]
  PIN rw0_rd_out[33]
    DIRECTION OUTPUT ;
    USE SIGNAL ;
    SHAPE ABUTMENT ;
    PORT
      LAYER met2 ;
      RECT 503.630 652.380 503.770 652.800 ;
    END
  END rw0_rd_out[33]
  PIN rw0_rd_out[34]
    DIRECTION OUTPUT ;
    USE SIGNAL ;
    SHAPE ABUTMENT ;
    PORT
      LAYER met2 ;
      RECT 518.810 652.380 518.950 652.800 ;
    END
  END rw0_rd_out[34]
  PIN rw0_rd_out[35]
    DIRECTION OUTPUT ;
    USE SIGNAL ;
    SHAPE ABUTMENT ;
    PORT
      LAYER met2 ;
      RECT 533.990 652.380 534.130 652.800 ;
    END
  END rw0_rd_out[35]
  PIN rw0_rd_out[36]
    DIRECTION OUTPUT ;
    USE SIGNAL ;
    SHAPE ABUTMENT ;
    PORT
      LAYER met2 ;
      RECT 549.170 652.380 549.310 652.800 ;
    END
  END rw0_rd_out[36]
  PIN rw0_rd_out[37]
    DIRECTION OUTPUT ;
    USE SIGNAL ;
    SHAPE ABUTMENT ;
    PORT
      LAYER met2 ;
      RECT 564.350 652.380 564.490 652.800 ;
    END
  END rw0_rd_out[37]
  PIN rw0_rd_out[38]
    DIRECTION OUTPUT ;
    USE SIGNAL ;
    SHAPE ABUTMENT ;
    PORT
      LAYER met2 ;
      RECT 579.530 652.380 579.670 652.800 ;
    END
  END rw0_rd_out[38]
  PIN rw0_rd_out[39]
    DIRECTION OUTPUT ;
    USE SIGNAL ;
    SHAPE ABUTMENT ;
    PORT
      LAYER met2 ;
      RECT 594.710 652.380 594.850 652.800 ;
    END
  END rw0_rd_out[39]
  PIN rw0_rd_out[40]
    DIRECTION OUTPUT ;
    USE SIGNAL ;
    SHAPE ABUTMENT ;
    PORT
      LAYER met2 ;
      RECT 609.890 652.380 610.030 652.800 ;
    END
  END rw0_rd_out[40]
  PIN rw0_rd_out[41]
    DIRECTION OUTPUT ;
    USE SIGNAL ;
    SHAPE ABUTMENT ;
    PORT
      LAYER met2 ;
      RECT 625.070 652.380 625.210 652.800 ;
    END
  END rw0_rd_out[41]
  PIN rw0_rd_out[42]
    DIRECTION OUTPUT ;
    USE SIGNAL ;
    SHAPE ABUTMENT ;
    PORT
      LAYER met2 ;
      RECT 640.250 652.380 640.390 652.800 ;
    END
  END rw0_rd_out[42]
  PIN rw0_rd_out[43]
    DIRECTION OUTPUT ;
    USE SIGNAL ;
    SHAPE ABUTMENT ;
    PORT
      LAYER met2 ;
      RECT 655.430 652.380 655.570 652.800 ;
    END
  END rw0_rd_out[43]
  PIN rw0_rd_out[44]
    DIRECTION OUTPUT ;
    USE SIGNAL ;
    SHAPE ABUTMENT ;
    PORT
      LAYER met2 ;
      RECT 670.610 652.380 670.750 652.800 ;
    END
  END rw0_rd_out[44]
  PIN rw0_rd_out[45]
    DIRECTION OUTPUT ;
    USE SIGNAL ;
    SHAPE ABUTMENT ;
    PORT
      LAYER met2 ;
      RECT 685.790 652.380 685.930 652.800 ;
    END
  END rw0_rd_out[45]
  PIN rw0_rd_out[46]
    DIRECTION OUTPUT ;
    USE SIGNAL ;
    SHAPE ABUTMENT ;
    PORT
      LAYER met2 ;
      RECT 700.970 652.380 701.110 652.800 ;
    END
  END rw0_rd_out[46]
  PIN rw0_rd_out[47]
    DIRECTION OUTPUT ;
    USE SIGNAL ;
    SHAPE ABUTMENT ;
    PORT
      LAYER met2 ;
      RECT 716.150 652.380 716.290 652.800 ;
    END
  END rw0_rd_out[47]
  PIN rw0_rd_out[48]
    DIRECTION OUTPUT ;
    USE SIGNAL ;
    SHAPE ABUTMENT ;
    PORT
      LAYER met2 ;
      RECT 731.330 652.380 731.470 652.800 ;
    END
  END rw0_rd_out[48]
  PIN rw0_rd_out[49]
    DIRECTION OUTPUT ;
    USE SIGNAL ;
    SHAPE ABUTMENT ;
    PORT
      LAYER met2 ;
      RECT 746.510 652.380 746.650 652.800 ;
    END
  END rw0_rd_out[49]
  PIN rw0_rd_out[50]
    DIRECTION OUTPUT ;
    USE SIGNAL ;
    SHAPE ABUTMENT ;
    PORT
      LAYER met2 ;
      RECT 761.690 652.380 761.830 652.800 ;
    END
  END rw0_rd_out[50]
  PIN rw0_rd_out[51]
    DIRECTION OUTPUT ;
    USE SIGNAL ;
    SHAPE ABUTMENT ;
    PORT
      LAYER met2 ;
      RECT 776.870 652.380 777.010 652.800 ;
    END
  END rw0_rd_out[51]
  PIN rw0_rd_out[52]
    DIRECTION OUTPUT ;
    USE SIGNAL ;
    SHAPE ABUTMENT ;
    PORT
      LAYER met2 ;
      RECT 792.050 652.380 792.190 652.800 ;
    END
  END rw0_rd_out[52]
  PIN rw0_rd_out[53]
    DIRECTION OUTPUT ;
    USE SIGNAL ;
    SHAPE ABUTMENT ;
    PORT
      LAYER met2 ;
      RECT 807.230 652.380 807.370 652.800 ;
    END
  END rw0_rd_out[53]
  PIN rw0_rd_out[54]
    DIRECTION OUTPUT ;
    USE SIGNAL ;
    SHAPE ABUTMENT ;
    PORT
      LAYER met2 ;
      RECT 822.410 652.380 822.550 652.800 ;
    END
  END rw0_rd_out[54]
  PIN rw0_rd_out[55]
    DIRECTION OUTPUT ;
    USE SIGNAL ;
    SHAPE ABUTMENT ;
    PORT
      LAYER met2 ;
      RECT 837.590 652.380 837.730 652.800 ;
    END
  END rw0_rd_out[55]
  PIN rw0_rd_out[56]
    DIRECTION OUTPUT ;
    USE SIGNAL ;
    SHAPE ABUTMENT ;
    PORT
      LAYER met2 ;
      RECT 852.770 652.380 852.910 652.800 ;
    END
  END rw0_rd_out[56]
  PIN rw0_rd_out[57]
    DIRECTION OUTPUT ;
    USE SIGNAL ;
    SHAPE ABUTMENT ;
    PORT
      LAYER met2 ;
      RECT 867.950 652.380 868.090 652.800 ;
    END
  END rw0_rd_out[57]
  PIN rw0_rd_out[58]
    DIRECTION OUTPUT ;
    USE SIGNAL ;
    SHAPE ABUTMENT ;
    PORT
      LAYER met2 ;
      RECT 883.130 652.380 883.270 652.800 ;
    END
  END rw0_rd_out[58]
  PIN rw0_rd_out[59]
    DIRECTION OUTPUT ;
    USE SIGNAL ;
    SHAPE ABUTMENT ;
    PORT
      LAYER met2 ;
      RECT 898.310 652.380 898.450 652.800 ;
    END
  END rw0_rd_out[59]
  PIN rw0_rd_out[60]
    DIRECTION OUTPUT ;
    USE SIGNAL ;
    SHAPE ABUTMENT ;
    PORT
      LAYER met2 ;
      RECT 913.490 652.380 913.630 652.800 ;
    END
  END rw0_rd_out[60]
  PIN rw0_rd_out[61]
    DIRECTION OUTPUT ;
    USE SIGNAL ;
    SHAPE ABUTMENT ;
    PORT
      LAYER met2 ;
      RECT 928.670 652.380 928.810 652.800 ;
    END
  END rw0_rd_out[61]
  PIN rw0_rd_out[62]
    DIRECTION OUTPUT ;
    USE SIGNAL ;
    SHAPE ABUTMENT ;
    PORT
      LAYER met2 ;
      RECT 943.850 652.380 943.990 652.800 ;
    END
  END rw0_rd_out[62]
  PIN rw0_rd_out[63]
    DIRECTION OUTPUT ;
    USE SIGNAL ;
    SHAPE ABUTMENT ;
    PORT
      LAYER met2 ;
      RECT 959.030 652.380 959.170 652.800 ;
    END
  END rw0_rd_out[63]
  PIN rw0_addr_in[0]
    DIRECTION INPUT ;
    USE SIGNAL ;
    SHAPE ABUTMENT ;
    PORT
      LAYER met3 ;
      RECT 0.000 526.170 0.900 526.470 ;
    END
  END rw0_addr_in[0]
  PIN rw0_addr_in[1]
    DIRECTION INPUT ;
    USE SIGNAL ;
    SHAPE ABUTMENT ;
    PORT
      LAYER met3 ;
      RECT 0.000 542.490 0.900 542.790 ;
    END
  END rw0_addr_in[1]
  PIN rw0_addr_in[2]
    DIRECTION INPUT ;
    USE SIGNAL ;
    SHAPE ABUTMENT ;
    PORT
      LAYER met3 ;
      RECT 0.000 558.810 0.900 559.110 ;
    END
  END rw0_addr_in[2]
  PIN rw0_addr_in[3]
    DIRECTION INPUT ;
    USE SIGNAL ;
    SHAPE ABUTMENT ;
    PORT
      LAYER met3 ;
      RECT 0.000 575.130 0.900 575.430 ;
    END
  END rw0_addr_in[3]
  PIN rw0_addr_in[4]
    DIRECTION INPUT ;
    USE SIGNAL ;
    SHAPE ABUTMENT ;
    PORT
      LAYER met3 ;
      RECT 0.000 591.450 0.900 591.750 ;
    END
  END rw0_addr_in[4]
  PIN rw0_addr_in[5]
    DIRECTION INPUT ;
    USE SIGNAL ;
    SHAPE ABUTMENT ;
    PORT
      LAYER met3 ;
      RECT 0.000 607.770 0.900 608.070 ;
    END
  END rw0_addr_in[5]
  PIN rw0_addr_in[6]
    DIRECTION INPUT ;
    USE SIGNAL ;
    SHAPE ABUTMENT ;
    PORT
      LAYER met3 ;
      RECT 1045.140 526.170 1046.040 526.470 ;
    END
  END rw0_addr_in[6]
  PIN rw0_addr_in[7]
    DIRECTION INPUT ;
    USE SIGNAL ;
    SHAPE ABUTMENT ;
    PORT
      LAYER met3 ;
      RECT 1045.140 542.490 1046.040 542.790 ;
    END
  END rw0_addr_in[7]
  PIN rw0_addr_in[8]
    DIRECTION INPUT ;
    USE SIGNAL ;
    SHAPE ABUTMENT ;
    PORT
      LAYER met3 ;
      RECT 1045.140 558.810 1046.040 559.110 ;
    END
  END rw0_addr_in[8]
  PIN rw0_addr_in[9]
    DIRECTION INPUT ;
    USE SIGNAL ;
    SHAPE ABUTMENT ;
    PORT
      LAYER met3 ;
      RECT 1045.140 575.130 1046.040 575.430 ;
    END
  END rw0_addr_in[9]
  PIN rw0_addr_in[10]
    DIRECTION INPUT ;
    USE SIGNAL ;
    SHAPE ABUTMENT ;
    PORT
      LAYER met3 ;
      RECT 1045.140 591.450 1046.040 591.750 ;
    END
  END rw0_addr_in[10]
  PIN rw0_we_in
    DIRECTION INPUT ;
    USE SIGNAL ;
    SHAPE ABUTMENT ;
    PORT
      LAYER met2 ;
      RECT 974.210 652.380 974.350 652.800 ;
    END
  END rw0_we_in
  PIN rw0_ce_in
    DIRECTION INPUT ;
    USE SIGNAL ;
    SHAPE ABUTMENT ;
    PORT
      LAYER met2 ;
      RECT 989.390 652.380 989.530 652.800 ;
    END
  END rw0_ce_in
  PIN rw0_clk
    DIRECTION INPUT ;
    USE SIGNAL ;
    SHAPE ABUTMENT ;
    PORT
      LAYER met2 ;
      RECT 1004.570 652.380 1004.710 652.800 ;
    END
  END rw0_clk
  PIN VSS
    DIRECTION INOUT ;
    USE GROUND ;
    PORT
      LAYER met4 ;
      RECT 2.160 4.080 3.360 648.720 ;
      RECT 13.040 4.080 14.240 648.720 ;
      RECT 23.920 4.080 25.120 648.720 ;
      RECT 34.800 4.080 36.000 648.720 ;
      RECT 45.680 4.080 46.880 648.720 ;
      RECT 56.560 4.080 57.760 648.720 ;
      RECT 67.440 4.080 68.640 648.720 ;
      RECT 78.320 4.080 79.520 648.720 ;
      RECT 89.200 4.080 90.400 648.720 ;
      RECT 100.080 4.080 101.280 648.720 ;
      RECT 110.960 4.080 112.160 648.720 ;
      RECT 121.840 4.080 123.040 648.720 ;
      RECT 132.720 4.080 133.920 648.720 ;
      RECT 143.600 4.080 144.800 648.720 ;
      RECT 154.480 4.080 155.680 648.720 ;
      RECT 165.360 4.080 166.560 648.720 ;
      RECT 176.240 4.080 177.440 648.720 ;
      RECT 187.120 4.080 188.320 648.720 ;
      RECT 198.000 4.080 199.200 648.720 ;
      RECT 208.880 4.080 210.080 648.720 ;
      RECT 219.760 4.080 220.960 648.720 ;
      RECT 230.640 4.080 231.840 648.720 ;
      RECT 241.520 4.080 242.720 648.720 ;
      RECT 252.400 4.080 253.600 648.720 ;
      RECT 263.280 4.080 264.480 648.720 ;
      RECT 274.160 4.080 275.360 648.720 ;
      RECT 285.040 4.080 286.240 648.720 ;
      RECT 295.920 4.080 297.120 648.720 ;
      RECT 306.800 4.080 308.000 648.720 ;
      RECT 317.680 4.080 318.880 648.720 ;
      RECT 328.560 4.080 329.760 648.720 ;
      RECT 339.440 4.080 340.640 648.720 ;
      RECT 350.320 4.080 351.520 648.720 ;
      RECT 361.200 4.080 362.400 648.720 ;
      RECT 372.080 4.080 373.280 648.720 ;
      RECT 382.960 4.080 384.160 648.720 ;
      RECT 393.840 4.080 395.040 648.720 ;
      RECT 404.720 4.080 405.920 648.720 ;
      RECT 415.600 4.080 416.800 648.720 ;
      RECT 426.480 4.080 427.680 648.720 ;
      RECT 437.360 4.080 438.560 648.720 ;
      RECT 448.240 4.080 449.440 648.720 ;
      RECT 459.120 4.080 460.320 648.720 ;
      RECT 470.000 4.080 471.200 648.720 ;
      RECT 480.880 4.080 482.080 648.720 ;
      RECT 491.760 4.080 492.960 648.720 ;
      RECT 502.640 4.080 503.840 648.720 ;
      RECT 513.520 4.080 514.720 648.720 ;
      RECT 524.400 4.080 525.600 648.720 ;
      RECT 535.280 4.080 536.480 648.720 ;
      RECT 546.160 4.080 547.360 648.720 ;
      RECT 557.040 4.080 558.240 648.720 ;
      RECT 567.920 4.080 569.120 648.720 ;
      RECT 578.800 4.080 580.000 648.720 ;
      RECT 589.680 4.080 590.880 648.720 ;
      RECT 600.560 4.080 601.760 648.720 ;
      RECT 611.440 4.080 612.640 648.720 ;
      RECT 622.320 4.080 623.520 648.720 ;
      RECT 633.200 4.080 634.400 648.720 ;
      RECT 644.080 4.080 645.280 648.720 ;
      RECT 654.960 4.080 656.160 648.720 ;
      RECT 665.840 4.080 667.040 648.720 ;
      RECT 676.720 4.080 677.920 648.720 ;
      RECT 687.600 4.080 688.800 648.720 ;
      RECT 698.480 4.080 699.680 648.720 ;
      RECT 709.360 4.080 710.560 648.720 ;
      RECT 720.240 4.080 721.440 648.720 ;
      RECT 731.120 4.080 732.320 648.720 ;
      RECT 742.000 4.080 743.200 648.720 ;
      RECT 752.880 4.080 754.080 648.720 ;
      RECT 763.760 4.080 764.960 648.720 ;
      RECT 774.640 4.080 775.840 648.720 ;
      RECT 785.520 4.080 786.720 648.720 ;
      RECT 796.400 4.080 797.600 648.720 ;
      RECT 807.280 4.080 808.480 648.720 ;
      RECT 818.160 4.080 819.360 648.720 ;
      RECT 829.040 4.080 830.240 648.720 ;
      RECT 839.920 4.080 841.120 648.720 ;
      RECT 850.800 4.080 852.000 648.720 ;
      RECT 861.680 4.080 862.880 648.720 ;
      RECT 872.560 4.080 873.760 648.720 ;
      RECT 883.440 4.080 884.640 648.720 ;
      RECT 894.320 4.080 895.520 648.720 ;
      RECT 905.200 4.080 906.400 648.720 ;
      RECT 916.080 4.080 917.280 648.720 ;
      RECT 926.960 4.080 928.160 648.720 ;
      RECT 937.840 4.080 939.040 648.720 ;
      RECT 948.720 4.080 949.920 648.720 ;
      RECT 959.600 4.080 960.800 648.720 ;
      RECT 970.480 4.080 971.680 648.720 ;
      RECT 981.360 4.080 982.560 648.720 ;
      RECT 992.240 4.080 993.440 648.720 ;
      RECT 1003.120 4.080 1004.320 648.720 ;
      RECT 1014.000 4.080 1015.200 648.720 ;
      RECT 1024.880 4.080 1026.080 648.720 ;
      RECT 1035.760 4.080 1036.960 648.720 ;
    END
  END VSS
  PIN VDD
    DIRECTION INOUT ;
    USE POWER ;
    PORT
      LAYER met4 ;
      RECT 2.160 4.080 3.360 648.720 ;
      RECT 13.040 4.080 14.240 648.720 ;
      RECT 23.920 4.080 25.120 648.720 ;
      RECT 34.800 4.080 36.000 648.720 ;
      RECT 45.680 4.080 46.880 648.720 ;
      RECT 56.560 4.080 57.760 648.720 ;
      RECT 67.440 4.080 68.640 648.720 ;
      RECT 78.320 4.080 79.520 648.720 ;
      RECT 89.200 4.080 90.400 648.720 ;
      RECT 100.080 4.080 101.280 648.720 ;
      RECT 110.960 4.080 112.160 648.720 ;
      RECT 121.840 4.080 123.040 648.720 ;
      RECT 132.720 4.080 133.920 648.720 ;
      RECT 143.600 4.080 144.800 648.720 ;
      RECT 154.480 4.080 155.680 648.720 ;
      RECT 165.360 4.080 166.560 648.720 ;
      RECT 176.240 4.080 177.440 648.720 ;
      RECT 187.120 4.080 188.320 648.720 ;
      RECT 198.000 4.080 199.200 648.720 ;
      RECT 208.880 4.080 210.080 648.720 ;
      RECT 219.760 4.080 220.960 648.720 ;
      RECT 230.640 4.080 231.840 648.720 ;
      RECT 241.520 4.080 242.720 648.720 ;
      RECT 252.400 4.080 253.600 648.720 ;
      RECT 263.280 4.080 264.480 648.720 ;
      RECT 274.160 4.080 275.360 648.720 ;
      RECT 285.040 4.080 286.240 648.720 ;
      RECT 295.920 4.080 297.120 648.720 ;
      RECT 306.800 4.080 308.000 648.720 ;
      RECT 317.680 4.080 318.880 648.720 ;
      RECT 328.560 4.080 329.760 648.720 ;
      RECT 339.440 4.080 340.640 648.720 ;
      RECT 350.320 4.080 351.520 648.720 ;
      RECT 361.200 4.080 362.400 648.720 ;
      RECT 372.080 4.080 373.280 648.720 ;
      RECT 382.960 4.080 384.160 648.720 ;
      RECT 393.840 4.080 395.040 648.720 ;
      RECT 404.720 4.080 405.920 648.720 ;
      RECT 415.600 4.080 416.800 648.720 ;
      RECT 426.480 4.080 427.680 648.720 ;
      RECT 437.360 4.080 438.560 648.720 ;
      RECT 448.240 4.080 449.440 648.720 ;
      RECT 459.120 4.080 460.320 648.720 ;
      RECT 470.000 4.080 471.200 648.720 ;
      RECT 480.880 4.080 482.080 648.720 ;
      RECT 491.760 4.080 492.960 648.720 ;
      RECT 502.640 4.080 503.840 648.720 ;
      RECT 513.520 4.080 514.720 648.720 ;
      RECT 524.400 4.080 525.600 648.720 ;
      RECT 535.280 4.080 536.480 648.720 ;
      RECT 546.160 4.080 547.360 648.720 ;
      RECT 557.040 4.080 558.240 648.720 ;
      RECT 567.920 4.080 569.120 648.720 ;
      RECT 578.800 4.080 580.000 648.720 ;
      RECT 589.680 4.080 590.880 648.720 ;
      RECT 600.560 4.080 601.760 648.720 ;
      RECT 611.440 4.080 612.640 648.720 ;
      RECT 622.320 4.080 623.520 648.720 ;
      RECT 633.200 4.080 634.400 648.720 ;
      RECT 644.080 4.080 645.280 648.720 ;
      RECT 654.960 4.080 656.160 648.720 ;
      RECT 665.840 4.080 667.040 648.720 ;
      RECT 676.720 4.080 677.920 648.720 ;
      RECT 687.600 4.080 688.800 648.720 ;
      RECT 698.480 4.080 699.680 648.720 ;
      RECT 709.360 4.080 710.560 648.720 ;
      RECT 720.240 4.080 721.440 648.720 ;
      RECT 731.120 4.080 732.320 648.720 ;
      RECT 742.000 4.080 743.200 648.720 ;
      RECT 752.880 4.080 754.080 648.720 ;
      RECT 763.760 4.080 764.960 648.720 ;
      RECT 774.640 4.080 775.840 648.720 ;
      RECT 785.520 4.080 786.720 648.720 ;
      RECT 796.400 4.080 797.600 648.720 ;
      RECT 807.280 4.080 808.480 648.720 ;
      RECT 818.160 4.080 819.360 648.720 ;
      RECT 829.040 4.080 830.240 648.720 ;
      RECT 839.920 4.080 841.120 648.720 ;
      RECT 850.800 4.080 852.000 648.720 ;
      RECT 861.680 4.080 862.880 648.720 ;
      RECT 872.560 4.080 873.760 648.720 ;
      RECT 883.440 4.080 884.640 648.720 ;
      RECT 894.320 4.080 895.520 648.720 ;
      RECT 905.200 4.080 906.400 648.720 ;
      RECT 916.080 4.080 917.280 648.720 ;
      RECT 926.960 4.080 928.160 648.720 ;
      RECT 937.840 4.080 939.040 648.720 ;
      RECT 948.720 4.080 949.920 648.720 ;
      RECT 959.600 4.080 960.800 648.720 ;
      RECT 970.480 4.080 971.680 648.720 ;
      RECT 981.360 4.080 982.560 648.720 ;
      RECT 992.240 4.080 993.440 648.720 ;
      RECT 1003.120 4.080 1004.320 648.720 ;
      RECT 1014.000 4.080 1015.200 648.720 ;
      RECT 1024.880 4.080 1026.080 648.720 ;
      RECT 1035.760 4.080 1036.960 648.720 ;
    END
  END VDD
  OBS
    LAYER met1 ;
    RECT 0 0 1046.040 652.800 ;
    LAYER met2 ;
    RECT 0 0 1046.040 652.800 ;
    LAYER met3 ;
    RECT 0 0 1046.040 652.800 ;
    LAYER met4 ;
    RECT 0 0 1046.040 652.800 ;
  END
END fakeram_64x2048_1rw

END LIBRARY
